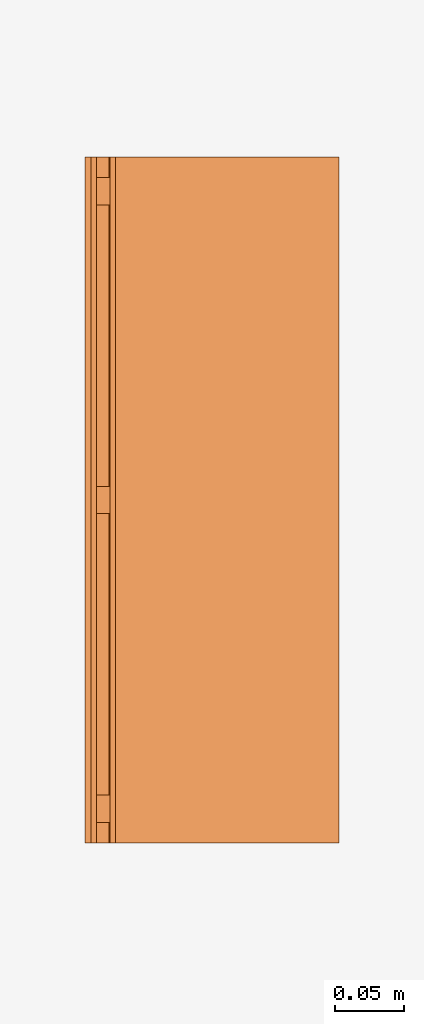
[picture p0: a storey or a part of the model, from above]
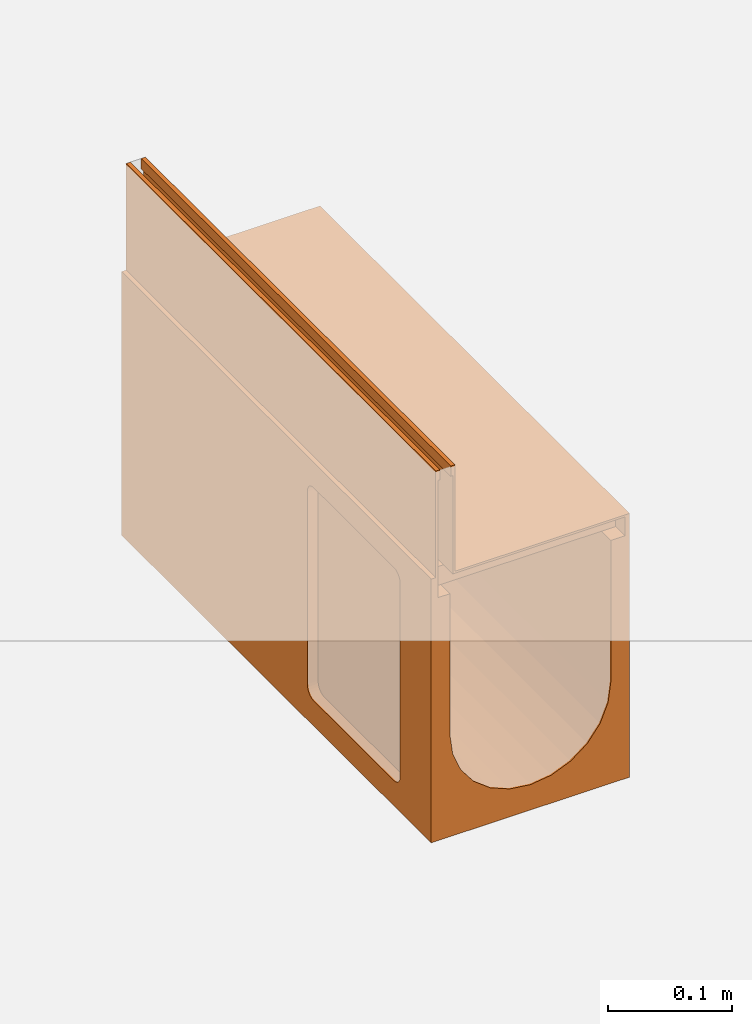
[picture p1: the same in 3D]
Properties of the parts of a building model (IFC2X3)

# File
Description: ViewDefinition [CoordinationView]
File name: 24154 - No 10.1J Constant Depth Channel - 500mm LG - Invert Depth 235mm.ifc
Time: 2013-10-30T13:30:35
Written by: Autodesk Revit 2013
Made in: 20120221_2030(x64)

# IfcProject, Project Number
LongName: Project Name; Phase: Project Status

# IfcSite, Default
RefLatitude: 42, 21, 30, 344238; RefLongitude: -71, -3, -35, -194702; RefElevation: 0 mm

# IfcBuilding
Pset_BuildingCommon - NumberOfStoreys: 1
Other - Project Status: Project Status; Client Name: Owner; Project Name: Project Name; Project Address: ## Street City, State Zip; Project Issue Date: Issue Date; Project Number: Project Number

# IfcBuildingStorey, Level 1
LongName: Level 1; Elevation: 0 mm
Graphics - Symbol: M_Level Head - Circle: M_Level Head - Circle; Color: 0; Symbol at End 1 Default: no; Symbol at End 2 Default: yes; Line Weight: 1; Line Pattern: Center
Constraints - Elevation Base: 0; Elevation: 0 mm
Identity Data - Building Story: yes; Name: Level 1; Structural: no
Dimensions - Computation Height: 0 mm

# IfcBuildingElementProxy: 24154 - No 10.1J Constant Depth Channel - 500mm LG - Invert Depth 235mm, Civil-Drainage-Channel-ACO-MultiDrain-M150DS-Brickslot-Channel-System:24154 - No 10.1J Constant Depth Channel - 500mm LG - Invert Depth 235mm:24154 - No 10.1J Constant Depth Channel - 500mm LG - Invert Depth 235mm:196059
In: Level 1
Material: Stainless Steel (F), Vienite® Synthetic Resin Concrete
Dimensions - Brickslot Access Unit Void Bottom Depth: 5895 mm; Volume: 7014628 mm3; FloorCut_Length: -500 mm; EndCap Position: 500 mm; Brickslot Access Unit Void Depth: 6000 mm; Brickslot Grating Void Depth: 0 mm; Length: 1000 mm; Brickslot Void Length: -500 mm; Custom_Void_Length: 0 mm; GratingLength: 0 mm; Depth: 260 mm; Floor Cut Gap: 105 mm; Length Drain: -500 mm; InvDepth: 160 mm; EndCap_Height: -260 mm; Floor cut gap depth for access unit: 105 mm; FloorCut_Depth: 260 mm; FloorCut_Width: 185 mm; FloorCut_HorPosition: 92.5 mm
Construction - 24187_Load Class C250 & D400_Brickslot_Access Unit_Stainless Steel_500mm Long: no; 23186_Load Class C250 & D400_Brickslot Grating_Stainless Steel_500mm Long: yes; 23185_Load Class C250 & D400_Brickslot Grating_Stainless Steel_1000mm Long: no; 23159_Universal Endcap (Male End): no; 23159_Universal Endcap (Female End): no; Constant Depth Channel_500: yes; 24158_Sump Unit: no; 24157_Shallow Depth Channel with seal: no; 24156_Shallow Depth Channel: no; Constant Depth Channel_1000: no
Phasing - Phase Created: New Construction
Constraints - Moves With Nearby Elements: no; Level: Level: Level 1
Pset_BuildingElementProxyCommon - Reference: 24154 - No 10.1J Constant Depth Channel - 500mm LG - Invert Depth 235mm
General - TagNumber: 0; SerialNumber: 0
Model Properties - Brickslot Grating Product code 23186: Load Class C250/D400 -Brickslot Stainless Steel - 500mm long x 105mm high - 10mm Slot - Intake area 10000mm²/m - 3.8kg; Brickslot Grating Product code 23185: N/A; End Cap Product code 23219: No. 306 Universal End Cap - 185mm wide x 310mm long - Spigot Ø110mm x 50mm long - Silver - Co-Polymer Polypropylene - 0.3kg; Brickslot Access Unit Product code 23187: Load Class C250/D400 - Brickslot Access Unit Stainless Steel - 500mm long x 105mm high - 10mm Slot - Intake area 10000mm²/m - 6.4kg
Identity Data - Model: ACO MultiDrain MDS Brickslot - M150DS; Installation guidelines: http://www.aco.co.uk/download.php?id=173; Fax: +44 (0)1462 815895; Manufacturer: ACO Technologies plc - ACO Water Management Division; Watermarked By: www.aco.co.uk; Type Comments: ACO MultiDrain M150DS 10.1J Constant Depth Channel 500mm Long; Watermarked With: BIM Manager Premium Suite; Watermark 1: This file is the property of ACO Technologies PLC; Product Code: 24154; Watermark 2: This file is water marked and users are prohibited to reproduce, adapt, distribute this information; Telephone: +44 (0)1462 816666; Assembly Description: Rain Water Drainage; OmniClass Number: 23.70.50.24; Maintenance guidelines: http://www.aco.co.uk/download.php?id=173; Model Description: Channel drainage system; Cost: 0; OmniClass Title: Rainwater Removal; Price: POA - contact ACO; e-mail Technical: technical@aco.co.uk; Address: ACO Business Park, Hitchin Road, Shefford, Bedfordshire, United Kingdom SG17 5TE; Assembly Code: D2040; e-mail Sales: customersupport@aco.co.uk; URL: www.aco.co.uk; Product Page URL: http://www.aco.co.uk/product_detail.php?id=58; Product brochure: http://www.aco.co.uk/download.php?id=173
Data - Concrete Surround Volume - Load Class D 400 - Concrete Pavement: 0.23m³/m; Channel C.S.A: 0.026m²; Pre-formed Outlet Ø: N/A; Installation - Concrete Grade: Refer to brochure; Product Dimensions: 500mm x 185mm x 260mm (LxWxH); Concrete Surround Volume - Load Class B 125 - C 250 - Concrete Pavement: 0.16m³/m; Hydraulic Performance: http://www.aco.co.uk/download.php?id=173; ACO Hydraulic Design Software: http://www.acodesign.co.uk; Product Standard: BS EN 1433:2002, CE marked; Invert Depth: 235mm; Product Weight: 15.6 Kg; Concrete Surround Volume - Load Class A 15 - Concrete Pavement: 0.10m³/m; Load Class: A 15 - D 400
Green Building Properties - Channel Recyclable: Fully recyclable; Edge Rail Recycled Material Content: Between 40% - 90%; Channel Recycled Material Content: 20% minimum; Edge Rail Recyclable: Fully recyclable
Materials and Finishes - Edge Rail Colour: Self; Channel Colour: Brown; Edge Rail Material: Stainless Steel Grade 304; Channel Material: Vienite® Synthetic Resin Concrete
Other - Revision: 1; CreatedBy: www.aco.co.uk

# IfcOpeningElement: Recess (2)
In: Level 1
Dimensions - Area: 25000000 mm2; Volume: 9975005000 mm3; Thickness: 400 mm; Perimeter: 20000 mm
Constraints - Level: Level: Level 1; Height Offset From Level: 0 mm; Related to Mass: no; Room Bounding: yes
Phasing - Phase Created: New Construction
Structural - Enable Analytical Model: no; Structural: no
Construction - Function: 0; Default Thickness: 400 mm
Analytical Properties - Heat Transfer Coefficient (U): 2.0925; Thermal Resistance (R): 0.477897; Absorptance: 0.1; Thermal mass: 543920; Roughness: 1
Graphics - Coarse Scale Fill Color: 0
Materials and Finishes - Structural Material: Earth

# IfcSlab: Floor:Generic Floor - 400mm, Floor:Generic Floor - 400mm:193825
In: Level 1
PredefinedType: FLOOR; Material: Earth 400 mm
Dimensions - Area: 25000000 mm2; Volume: 9975005000 mm3; Thickness: 400 mm; Perimeter: 20000 mm
Constraints - Level: Level: Level 1; Height Offset From Level: 0 mm; Related to Mass: no; Room Bounding: yes
Phasing - Phase Created: New Construction
Structural - Enable Analytical Model: no; Structural: no
Pset_SlabCommon - Reference: Generic Floor - 400mm; IsExternal: no; LoadBearing: yes
Construction - Function: 0; Default Thickness: 400 mm
Analytical Properties - Heat Transfer Coefficient (U): 2.0925; Thermal Resistance (R): 0.477897; Absorptance: 0.1; Thermal mass: 543920; Roughness: 1
Graphics - Coarse Scale Fill Color: 0
Materials and Finishes - Structural Material: Earth
